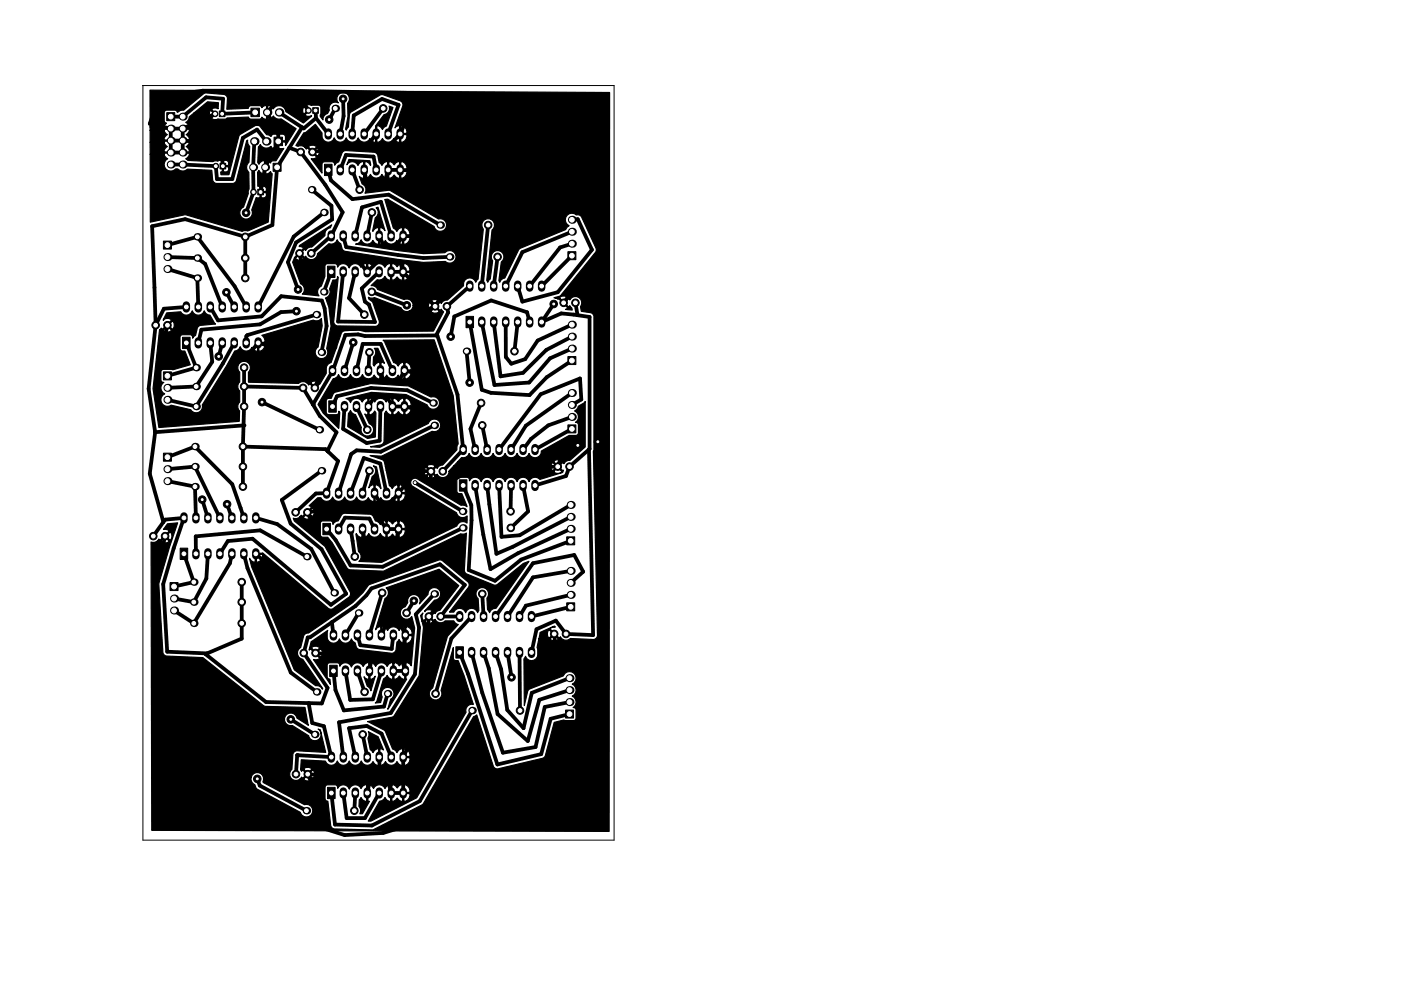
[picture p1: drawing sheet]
<svg xmlns="http://www.w3.org/2000/svg" width="297mm" height="210mm" viewBox="0 0 297 210" stroke-linecap="round" stroke-linejoin="round" font-family="sans-serif">
<path d="M30.2 18.1h100v160.1h-99.9v-160.1" fill="none" stroke="#000" stroke-width=".21"/>
<g fill="#000" stroke="#000" stroke-width=".21">
<path d="M35.3 23.9h1.7v1.7h-1.7zM46.5 23.5h1.2v1.2h-1.2zM46.6 34.6h1.3v1.2h-1.3zM53.2 22.9h1.8v1.8h-1.8zM57.9 34.6h1.7v1.7h-1.7zM58.1 29.1h1.8v1.8h-1.8zM66.3 22.8h1.2v1.2h-1.2zM68.8 34.8h1.6v2.4h-1.6zM34.6 51.1h1.7v1.7h-1.7zM54.6 40.1h1.3v1.2h-1.3zM69.4 56.5h1.6v2.4h-1.6zM120.4 53.4h1.7v1.7h-1.7z"/>
<path d="M38.7 71.5h1.6v2.4h-1.6zM98.8 67.1h1.6v2.4h-1.6zM120.4 75.6h1.7v1.7h-1.7zM34.6 78.9h1.7v1.7h-1.7zM34.6 96.1h1.7v1.7h-1.7zM69.7 85h1.6v2.4h-1.6zM120.4 90.1h1.7v1.7h-1.7zM38.2 116.3h1.6v2.4h-1.6zM68.4 111h1.6v2.4h-1.6zM97.4 101.8h1.6v2.4h-1.6zM120.2 113.9h1.6v1.7h-1.6zM36 123.6h1.7v1.7h-1.7z"/>
<path d="M96.7 137.2h1.5v2.4h-1.5zM120.2 127.9h1.6v1.7h-1.6zM69.9 141.1h1.6v2.4h-1.6zM119.9 150.6h1.7v1.7h-1.7zM69.4 167h1.6v2.4h-1.6z"/>
<circle cx="45.6" cy="24.1" r=".6"/>
<circle cx="45.7" cy="35.2" r=".6"/>
<circle cx="63.7" cy="32.2" r=".8"/>
<circle cx="65.4" cy="23.4" r=".6"/>
<circle cx="66.2" cy="32.2" r=".8"/>
<circle cx="69.8" cy="25.4" r=".8"/>
<circle cx="72.7" cy="21" r=".8"/>
<circle cx="81.2" cy="23" r=".8"/>
<circle cx="52" cy="59" r=".8"/>
<circle cx="52" cy="50.2" r=".8"/>
<circle cx="52" cy="54.7" r=".8"/>
<circle cx="52.2" cy="45.1" r=".8"/>
<circle cx="53.7" cy="40.7" r=".6"/>
<circle cx="63.5" cy="53.7" r=".8"/>
<circle cx="66" cy="53.7" r=".8"/>
<circle cx="76.2" cy="40.2" r=".8"/>
<circle cx="78.8" cy="45.1" r=".8"/>
<circle cx="103.5" cy="47.7" r=".8"/>
<circle cx="105.5" cy="54.5" r=".8"/>
<circle cx="33" cy="69" r=".8"/>
<circle cx="35.5" cy="69" r=".8"/>
<circle cx="46.4" cy="75.6" r=".8"/>
<circle cx="48" cy="62" r=".8"/>
<circle cx="51.8" cy="78" r=".8"/>
<circle cx="62.8" cy="66" r=".8"/>
<circle cx="63.2" cy="61.4" r=".8"/>
<circle cx="74.9" cy="72.6" r=".8"/>
<circle cx="77.2" cy="66.7" r=".8"/>
<circle cx="78.3" cy="74.7" r=".8"/>
<circle cx="78.8" cy="61.9" r=".8"/>
<circle cx="86.2" cy="64.8" r=".8"/>
<circle cx="92.2" cy="65" r=".8"/>
<circle cx="94.7" cy="65" r=".8"/>
<circle cx="95.5" cy="71.4" r=".8"/>
<circle cx="109.1" cy="74.5" r=".8"/>
<circle cx="117.4" cy="64.5" r=".8"/>
<circle cx="119.5" cy="64.2" r=".8"/>
<circle cx="122" cy="64.2" r=".8"/>
<circle cx="51.5" cy="99" r=".8"/>
<circle cx="51.5" cy="94.7" r=".8"/>
<circle cx="51.8" cy="82" r=".8"/>
<circle cx="51.8" cy="86.2" r=".8"/>
<circle cx="55.5" cy="85.3" r=".8"/>
<circle cx="64.2" cy="82.3" r=".8"/>
<circle cx="66.7" cy="82.3" r=".8"/>
<circle cx="77.9" cy="91.2" r=".8"/>
<circle cx="78.3" cy="99.9" r=".8"/>
<circle cx="91.4" cy="100" r=".8"/>
<circle cx="93.9" cy="100" r=".8"/>
<circle cx="99.6" cy="81.2" r=".8"/>
<circle cx="102" cy="85.5" r=".8"/>
<circle cx="102.2" cy="90.2" r=".8"/>
<circle cx="118.2" cy="99" r=".8"/>
<circle cx="120.7" cy="99" r=".8"/>
<circle cx="122.5" cy="94.5" r=".8"/>
<circle cx="126.7" cy="93.7" r=".8"/>
<circle cx="32.5" cy="113.7" r=".8"/>
<circle cx="35" cy="113.7" r=".8"/>
<circle cx="42.9" cy="106" r=".8"/>
<circle cx="48.1" cy="107" r=".8"/>
<circle cx="51.5" cy="103.2" r=".8"/>
<circle cx="62.7" cy="108.7" r=".8"/>
<circle cx="65.2" cy="108.7" r=".8"/>
<circle cx="75.2" cy="118.1" r=".8"/>
<circle cx="88" cy="102.4" r=".4"/>
<circle cx="108.2" cy="108.5" r=".8"/>
<circle cx="108.3" cy="112" r=".8"/>
<circle cx="51.2" cy="127.7" r=".8"/>
<circle cx="51.2" cy="123.5" r=".8"/>
<circle cx="51.2" cy="132.2" r=".8"/>
<circle cx="64.4" cy="138.5" r=".8"/>
<circle cx="66.9" cy="138.5" r=".8"/>
<circle cx="81" cy="125.8" r=".8"/>
<circle cx="86.2" cy="130" r=".8"/>
<circle cx="87.7" cy="127.5" r=".8"/>
<circle cx="90.9" cy="130.8" r=".8"/>
<circle cx="93.4" cy="130.8" r=".8"/>
<circle cx="102.2" cy="126" r=".8"/>
<circle cx="117.5" cy="134.5" r=".8"/>
<circle cx="120" cy="134.5" r=".8"/>
<circle cx="61.6" cy="152.6" r=".8"/>
<circle cx="76.9" cy="155.8" r=".8"/>
<circle cx="77.3" cy="146.8" r=".8"/>
<circle cx="92.3" cy="147.2" r=".8"/>
<circle cx="108.4" cy="143.7" r=".8"/>
<circle cx="110.3" cy="150.7" r=".8"/>
<circle cx="54.5" cy="165.2" r=".8"/>
<circle cx="62.7" cy="164.2" r=".8"/>
<circle cx="65.2" cy="164.2" r=".8"/>
<circle cx="75.1" cy="172" r=".8"/>
</g>
<g fill="#000">
<circle cx="36.2" cy="27.3" r=".85"/>
<circle cx="36.2" cy="29.8" r=".85"/>
<circle cx="36.2" cy="34.9" r=".85"/>
<circle cx="36.2" cy="32.4" r=".85"/>
<circle cx="38.7" cy="34.9" r=".85"/>
<circle cx="38.7" cy="24.7" r=".85"/>
<circle cx="38.7" cy="32.4" r=".85"/>
<circle cx="38.7" cy="29.8" r=".85"/>
<circle cx="38.7" cy="27.3" r=".85"/>
<circle cx="53.7" cy="35.5" r=".85"/>
<circle cx="53.9" cy="30" r=".9"/>
<circle cx="56.2" cy="35.5" r=".85"/>
<circle cx="56.5" cy="30" r=".9"/>
<circle cx="56.6" cy="23.8" r=".9"/>
<circle cx="57.9" cy="26.2" r=".4"/>
<circle cx="59.2" cy="23.8" r=".9"/>
<circle cx="71.1" cy="23" r=".8"/>
<circle cx="100.3" cy="36.9" r=".4"/>
<circle cx="35.5" cy="54.5" r=".85"/>
<circle cx="35.5" cy="57.1" r=".85"/>
<circle cx="41.8" cy="54.7" r=".8"/>
<circle cx="41.8" cy="50.2" r=".8"/>
<circle cx="41.8" cy="59" r=".8"/>
<circle cx="66.1" cy="40.2" r=".8"/>
<circle cx="68.7" cy="45.1" r=".8"/>
<circle cx="93.3" cy="47.7" r=".8"/>
<circle cx="95.3" cy="54.5" r=".8"/>
<circle cx="121.2" cy="49.2" r=".85"/>
<circle cx="121.2" cy="46.6" r=".85"/>
<circle cx="121.2" cy="51.7" r=".85"/>
<circle cx="41.6" cy="78" r=".8"/>
<circle cx="67.1" cy="66.7" r=".8"/>
<circle cx="68.2" cy="74.7" r=".8"/>
<circle cx="68.6" cy="77.5" r=".4"/>
<circle cx="68.7" cy="61.9" r=".8"/>
<circle cx="98.9" cy="74.5" r=".8"/>
<circle cx="121.2" cy="74" r=".85"/>
<circle cx="121.2" cy="71.4" r=".85"/>
<circle cx="121.2" cy="68.9" r=".85"/>
<circle cx="35.5" cy="84.8" r=".85"/>
<circle cx="35.5" cy="99.5" r=".85"/>
<circle cx="35.5" cy="82.3" r=".85"/>
<circle cx="41.3" cy="99" r=".8"/>
<circle cx="41.3" cy="94.7" r=".8"/>
<circle cx="41.6" cy="86.2" r=".8"/>
<circle cx="41.6" cy="82" r=".8"/>
<circle cx="51.6" cy="90.3" r=".4"/>
<circle cx="66.3" cy="85.8" r=".4"/>
<circle cx="67.7" cy="91.2" r=".8"/>
<circle cx="68.2" cy="99.9" r=".8"/>
<circle cx="91.8" cy="85.5" r=".8"/>
<circle cx="92.1" cy="90.2" r=".8"/>
<circle cx="121.2" cy="83.4" r=".85"/>
<circle cx="121.2" cy="85.9" r=".85"/>
<circle cx="121.2" cy="88.5" r=".85"/>
<circle cx="127.9" cy="93.5" r=".4"/>
<circle cx="35.5" cy="102.1" r=".85"/>
<circle cx="41.3" cy="103.2" r=".8"/>
<circle cx="65.1" cy="118.1" r=".8"/>
<circle cx="98.1" cy="108.5" r=".8"/>
<circle cx="98.1" cy="112" r=".8"/>
<circle cx="121" cy="109.7" r=".85"/>
<circle cx="121" cy="107.1" r=".85"/>
<circle cx="121" cy="112.2" r=".85"/>
<circle cx="36.9" cy="129.5" r=".85"/>
<circle cx="36.9" cy="127" r=".85"/>
<circle cx="41.1" cy="132.2" r=".8"/>
<circle cx="41.1" cy="127.7" r=".8"/>
<circle cx="41.1" cy="123.5" r=".8"/>
<circle cx="70.9" cy="125.8" r=".8"/>
<circle cx="76" cy="130" r=".8"/>
<circle cx="92.1" cy="126" r=".8"/>
<circle cx="121" cy="123.7" r=".85"/>
<circle cx="121" cy="121.1" r=".85"/>
<circle cx="121" cy="126.2" r=".85"/>
<circle cx="66.7" cy="155.8" r=".8"/>
<circle cx="67.1" cy="146.8" r=".8"/>
<circle cx="82.2" cy="147.2" r=".8"/>
<circle cx="100.1" cy="150.7" r=".8"/>
<circle cx="120.8" cy="149" r=".85"/>
<circle cx="120.8" cy="146.4" r=".85"/>
<circle cx="120.8" cy="143.9" r=".85"/>
<circle cx="63" cy="160.2" r=".4"/>
<circle cx="65" cy="172" r=".8"/>
</g>
<g fill="none" stroke="#000" stroke-width="1.6">
<path d="M69.6 28v.8M72.1 28v.8M72.1 35.6v.8M74.7 28v.8M74.7 35.6v.8M77.2 28v.8M77.2 35.6v.8M79.8 28v.8M79.8 35.6v.8M82.3 28v.8M82.3 35.6v.8M84.8 28v.8"/>
<path d="M84.8 35.6v.8M70.2 49.7v.8M72.8 49.7v.8M72.8 57.3v.8M75.3 49.7v.8M75.3 57.3v.8M77.8 49.7v.8M77.8 57.3v.8M80.4 49.7v.8M80.4 57.3v.8M82.9 49.7v.8M82.9 57.3v.8"/>
<path d="M85.5 49.7v.8M85.5 57.3v.8M39.5 64.7v.8M42 64.7v.8M42 72.3v.8M44.6 64.7v.8M44.6 72.3v.8M47.1 64.7v.8M47.1 72.3v.8M49.7 64.7v.8M49.7 72.3v.8M52.2 64.7v.8"/>
<path d="M52.2 72.3v.8M54.7 64.7v.8M54.7 72.3v.8M70.5 78.2v.8M73 78.2v.8M75.6 78.2v.8M78.1 78.2v.8M80.7 78.2v.8M83.2 78.2v.8M85.7 78.2v.8M99.6 60.3v.8M102.1 60.3v.8"/>
<path d="M102.1 67.9v.8M104.7 60.3v.8M104.7 67.9v.8M107.2 60.3v.8M107.2 67.9v.8M109.8 60.3v.8M109.8 67.9v.8M112.3 60.3v.8M112.3 67.9v.8M114.8 60.3v.8M114.8 67.9v.8M73 85.8v.8"/>
<path d="M75.6 85.8v.8M78.1 85.8v.8M80.7 85.8v.8M83.2 85.8v.8M85.7 85.8v.8M98.2 95v.8M100.7 95v.8M103.3 95v.8M105.8 95v.8M108.4 95v.8M110.9 95v.8M113.4 95v.8"/>
<path d="M39 109.5v.8M41.5 109.5v.8M41.5 117.1v.8M44.1 109.5v.8M44.1 117.1v.8M46.6 109.5v.8M46.6 117.1v.8M49.2 109.5v.8M49.2 117.1v.8M51.7 109.5v.8M51.7 117.1v.8M54.2 109.5v.8"/>
<path d="M54.2 117.1v.8M69.3 104.2v.8M71.8 104.2v.8M71.8 111.8v.8M74.3 104.2v.8M74.3 111.8v.8M76.9 104.2v.8M76.9 111.8v.8M79.4 104.2v.8M79.4 111.8v.8M82 104.2v.8M82 111.8v.8"/>
<path d="M84.5 104.2v.8M84.5 111.8v.8M100.7 102.6v.8M103.3 102.6v.8M105.8 102.6v.8M108.4 102.6v.8M110.9 102.6v.8M113.4 102.6v.8M70.7 134.3v.8M73.2 134.3v.8M75.8 134.3v.8M78.3 134.3v.8"/>
<path d="M80.9 134.3v.8M83.4 134.3v.8M85.9 134.3v.8M97.4 130.4v.8M100 130.4v.8M100 138v.8M102.5 130.4v.8M102.5 138v.8M105.1 130.4v.8M105.1 138v.8M107.6 130.4v.8M107.6 138v.8"/>
<path d="M110.1 130.4v.8M110.1 138v.8M112.7 130.4v.8M112.7 138v.8M73.2 141.9v.8M75.8 141.9v.8M78.3 141.9v.8M80.9 141.9v.8M83.4 141.9v.8M85.9 141.9v.8M70.3 160.2v.8M72.8 160.2v.8"/>
<path d="M72.8 167.8v.8M75.3 160.2v.8M75.3 167.8v.8M77.9 160.2v.8M77.9 167.8v.8M80.4 160.2v.8M80.4 167.8v.8M83 160.2v.8M83 167.8v.8M85.5 160.2v.8M85.5 167.8v.8"/>
</g>
<g fill="none" stroke="#000" stroke-width=".8">
<path d="M88.7 19.7l-27.7-.5h-18l-9.3 1.3-2 5.7 4.5 1.1M88.7 19.7l-3.9 8.7-2.6 2.9-4.6-.1M88.7 19.7l37.5 18.8 1.6 16.2M36.2 27.3h2.5M36.2 27.3v5.1h2.5v-5.1M36.2 29.8h2.5l8 .7 .6 4.7M45.6 24.1l-6.9 3.2M53.9 30l-.2 5.5v5.2l-1.5 4.4M54.1 23.8l-7 .3 .2-3.2-3.6-.3-5 4.1h-2.5M56.5 30l-2-2.5-3 1.7-2.2 8.8h-3.3l-.3-2.8-9.5-.3M57.9 26.2l-6.3 .1-5.3 4.2M59.2 23.8l5.2 3.4 2.6-2.2"/>
<path d="M61.3 31.3l2.4 .9 5.3 7 3.7 5.8-2.5 5.1-4.2 3.6M64 27l-5.3 8.5-1 12.2-5.7 2.5M65.4 23.4l-1.2-2.1-5.5 .2-2.1 2.3 2.4 4.7v1.5l-2.8 5.5-.9 5.2M66.9 23.4l.1 1.6M67 25l2.6 3.4M69.6 36l.5 2.2 4.6 4 7.7-.9 10.9 6.4M71.1 23l-1.3 2.4M72.1 36l1.3-3.1 5.8 .3 .6 2.8M72.7 21l.1 3.6-.7 3.8M74.7 36l1.6 4.2M74.7 28.4l.3-3.9 6-3.5 3.5 1.2-2.2 6.2M77.2 36l.4 2.1 3.6 1.5 1.1-3.6h2.5l15.5 .9"/>
<path d="M77.6 31.2l-7.2 .4-4.1 .6M79.8 28.4l-2.2 2.8M81.3 23l-4.1 5.4M102.8 26.8v.3l.1-.3-6.2 23.7-11.2-.4-1.7 2.3-2.5-.5-.9-1.8M35.5 52l6.3-1.8 7.9 10.5 2.5 4.4M35.5 54.5l6.3 .2 1.7 1.3 3.6 9.1M35.5 57.1l6.3 1.9 .2 6.1M52 50.2v8.8M52 50.2l-12.7-3.7-7 1.5 .7 21M63.5 53.7l.5 2.3 3.5-.3 8-1.1 2.3 3.1 2.6-2.5 4.4 .2 .7 2.3M66.1 40.2l4.2 3.4 .1 2.9-7.6 4.9-1.8 4.2 2.2 5.8M68.7 45.1l-6.4 5.1-7.6 14.9"/>
<path d="M70.2 57.7l-1.5 4.2M72.8 50.1l.6 2.3 11 1.7 5.4 .6 5.5-.2M72.8 57.7l-1.1 10.5 7.8 .1-1.3-3.7-.8-.6-.7-2.8 3.7-3.5M75.3 57.7l-1.3 5.5 3.3 3.5M75.3 50.1l1.4-6.1 4.1-1.2 2.1 7.3M78.8 45.1l-1 5M82.9 57.7h2.6M85.5 57.7l6.8 7.3M96.6 50.5l1.9 3.3-2.8 5.6-3.4 5.6M103.5 47.7l-1.4 13M105.5 54.5l-.8 6.2M121.2 54.2l-6.4 6.5"/>
<path d="M121.2 51.7l-2.4 .8-6.5 8.2M121.2 49.2l-10.4 4.3-3.6 7.2M121.2 46.6l1.3-.1 3 6.5-7.3 9-7.4 2-1-3.3M127.8 54.7l-3.8 3.5-4.5 6M127.8 54.7l.1 38.8M33 69l-1.5 13.5 1.4 9.2M35.5 69l-1.6 6.8-.5 6.6 .5 5 12.2 1.7 3.4-11.8 2.9-1.7 2.3-2.9 10 2.7 3.9 2.1M39.5 72.7l2.1 5.3-6.1 1.7M39.5 65.1l-4.8 .4-1.7 3.5M44.6 65.1l1.6 2.9 9.3-.9 4.1-4.3 8.7 1 .5 1.6 .5 3.8-1.1 5.5M44.6 72.7l.4 4-3.4 5.3-6.1 .3M47.1 72.7l-.7 2.9"/>
<path d="M48 62l1.7 3.1M49.7 72.7l-2.4 4.4-5.7 9.1-6.1-1.4M51.7 78v8.2l-.2 8.5M62.9 66l-3.3 .2-4.5 2.6-12.4 1.1-.7 2.8M67.1 66.7l-14.7 4.4-.2 .2v1.4M68.6 77.5l-1.9 4.8M74.9 72.6l-1.9 6M75.6 78.6l1.3-5.6h3.8l2.5 5.6M78.3 74.7l-.2 3.9M78.8 61.9l7.5 2.9M80.7 78.6l.7 2.4h3.1l1.2-2.4 6.6 1.5 2.7 8.2M92.3 65l-11.2 4.5-10 .4v3.8l-2.5 3.8"/>
<path d="M92.5 71.2h.2l4.3 12.5 1.2 11.7-4.3 4.6M92.5 71.2l-15.1 .1-1.5-.4-2.7 .2-2.6 7.5-4.3 7.2M98.9 74.5l.7 6.7M99.6 68.3l2.5 14.4 2 .6 8.2 .5 3.6-3.8 5.3-3.5M99.6 60.7l-4.9 4.3 .3 1.3-2.5 4.9M102.1 68.3l2.7 13.4 7.4-.5 4.4-5.2 4.6-2M104.7 68.3l1.4 11.5 4.8-.7 4.9-4.9 5.4-2.8M107.2 68.3v7.4l1.2 1.5 3-1 2.6-4 7.2-3.3M109.8 68.3l-.7 6.2M112.3 68.3l-.5-2.1-7.7-2.5-7.8 3.4-.8 4.3M117.4 64.5l-2.6 3.8 4.2-1.8 6 .7v28l-4.2 3.8-.8 2-6.6 2M122 64.2l.4 2.7"/>
<path d="M32.9 91.7h.1M32.9 91.7l-1.2 8.8 2.9 10.3M35.5 97l5.8-2.3 8 8 2.4 7.2M35.5 99.5l5.8-.5 5.3 10.9M51.5 94.7v8.5M51.5 94.7l17.5 .6 2.7 2.5-2.4 6.8-2.3 .1-4.3 4M51.6 90.3l-18.7 1.4M51.7 82l12.6 .3 3.5 5.9 3.6 3.5-2 4 .2-.3v.4M55.6 85.3l12.1 5.9M68.2 99.9l-8.5 6.2 1.9 5 6.6 5.4 5.2 9.5-3.3 2.3-16.5-14-5.3 .5-1.7 2.7M73 86.2l-.3 4.8 5 3 2.8-.5 .2-7.3M75.6 86.2l2.3 5"/>
<path d="M78.1 86.2l1.4-2.2h2.5l1.2 2.2h2.5l9.3 2.1M78.3 99.9l-1.4 4.7M91.8 85.5l-5.4-2.7-7.7-.5-7.3 1.8-.9 2.1M92.1 90.2l-11.4 5.6-5.1-.3-1.2 .8-2.6 8.3M95 88.3l-.8 4-11.3 14.3h-2.4M102 85.5l-2.2 5.5 .9 4.4M102.2 90.2l1.1 5.2M121.2 91l-7.8 4.4M121.2 88.5l-5 1.7-3.6 2.9-1.7 2.3M121.2 85.9l2-1.2-.2-4.4-8.4 3.3-8.8 11.8M121.2 83.4l-9.7 6.9-3.1 5.1M122.5 94.5l-3.3 1.7-1 2.8-18 .5-6.1 3.4-2.8-.8 .1-2.1-3.1-.1"/>
<path d="M124.9 95.4l.9 39.3-5.8-.2-2.2-2.8-4 1.8-1.1 4.9M127.9 93.5l.1 41.5-1.8 7.2-8.2-3-.5-4.7M127.9 93.5l-1.1 .2M32.5 113.7l2.5-3.5 4-.3-2.2 6.4-2.2 7.6 .9 14.4 8.4 .3M35 113.7l-2.3 10.3 .8 16.8 23.3 22.6 10.2 6.2M35.5 102.1l5.8 1.1 .2 6.7M39 117.5l2.1 6-4.2 .9M41.5 117.5v-3.7l13.7-1.3 9.9 5.6M42.9 106l1.2 3.9M44.1 117.5l-.4 5.2-2.6 5-4.2-.7M48.2 107l1 2.9M49.2 117.5l-.5 2-7.6 12.7-4.2-2.7"/>
<path d="M51.7 117.5l.8 3 9.2 22.2 5.4 4.1M54.2 109.9l4.6 1.3 7.2 5.3 4.9 9.3M71.8 112.2l1.3-2.4 5.2 .2 1.1 2.2M74.3 112.2l.9 5.9M74.3 104.6l2.8-7.4 3.5 1.1 1.4 6.3M78.7 107.8l3.3 4.4h2.5l-.8 4.3-6.2-1-.6-3.3M78.7 107.8l-5.3-.3-8.2 1.2 2.4 5.3 2.6 2.1 5 8.8-.4 2.1-5.7 3.9-14.9-13.4M79.4 104.6l1.1 2M80.5 106.6l-1.8 1.2M88 102.4l10.1 6.1M98.1 112l-17 8.2-6.8-.2-3.1-5.4-1.9-2.4M98.2 103l1.7 4.2 .1 3.2-.6 10.5 5.6 2.3 5.5-4.5 10.5-4"/>
<path d="M100.7 103l1.8 10.4 1.5 7.3 5.8-3.3 11.2-5.2M103.3 103l1.9 14.5 3.6-1.5 12.2-6.3M105.8 103l.5 10.9 3.9-.3 10.8-6.5M108.4 103l-.2 5.5M110.9 103l1.1 5.5-3.7 3.5M51.3 123.5v12l-7.4 3.1M66.9 138.5l11.9 1.4M70.4 132l.3 2.7M75.8 134.7l.6 2.2 6.7 .8 .3-3M76 130l-2.8 4.7M78.8 139.9l-.5 2.4M78.8 139.9l6.3 .1"/>
<path d="M80.9 134.7l1-2.4 2.9-.1 1.1 2.5-.8 5.3M81 125.8l-2.7 8.9M83 132.3l1.8-6.5 8.6-3.1 1.4 2.9-3.9 5.2-1.8 22.4-3.6 7.4v7.6h-2.5l-1-3.5-3.5 .5M85.1 140l.8 2.3h-2.5M87.7 127.5l-1.5 2.5M92.1 126l-4 4.3 .7 2.8-.8 9.9-5.2 8.3-10.9 1.9 .9 7.4M97.4 138.4l1.8 4.6 6.2 19.2 9.4-2.2 2-7.5 4-1M97.4 130.8h-4l5.1-6.7-5.2-4.4-14.6 5.1-1 1.5-2.3 2.3-9.7 6.6h-.4l-.9 3.3 5 7.4-1.2 3.3-11.8-.3-12.8-10.1 .3-.2M100 138.4l2.2 8.6 4.4 12.7 6.9-1.2 2-8.5 5.3-1M100 130.8l-4.3 4.7-3.3 11.7M102.2 126l.3 4.8M102.5 138.4l1.1 3.4 1.9 9.7 6.4 5.7 2.5-8.7 6.4-2.1"/>
<path d="M105.1 138.4l1.1 3.6 1.3 8.6 3.5 3.9 1.8-7.5 8-3.1M107.6 138.4l.9 5.3M110.1 138.4l.1 12.3M121 128.7l-8.3 2.1M121 126.2l-9.5 2.3-1.4 2.3M121 123.7l2.6-2.4-1.8-3.6-8.8 1.8-7.9 11.3M121 121.1l-8 1.4-5.4 8.3M61.7 152.6l5 3.2M65.4 149.2l.8 4.2 2.5 .7 1.6 6.5-7.3-.4-.3 4M70.7 142.3l.4 4.1 1.8 4.3 8.5-.8 .8-2.7M73.2 142.3l1.1 6.2 4.7-.1 1.9-6.1M75.8 142.3l1.5 4.5"/>
<path d="M76.9 155.8l1 4.8M100.1 150.7l-11.1 19.3-10.2 5.1-7.8-.2-.7-6.7M126.3 142l-4.5 22.3-40.5 12.4-8.2 .5-6-1.9-.1-7.1-1.7-4 13.2 1M54.6 165.2l.5 1.5 9.9 5.3M72.8 168.2l.7 5.4h3.9l3-5.4M75.3 168.2l-.2 3.8M75.3 160.6l-1.3-6.1 3.8-.5 3.1 1.7 2.1 4.9M78.5 165.2l-.6 3M80.4 160.6l.1 4.4"/>
</g>
<path d="M31.8 19.1l97.4 .5-.1 156.8-96.9-.2v-11.2h21l.2 1 .6 .5 .6 .9 9.1 5v.1a1.35 1.35 0 0 0 1.7 .8 1.35 1.35 0 0 0 .8-1.7 1.35 1.35 0 0 0-1.6-.9l-8.8-4.7-.1-.2a1.34 1.34 0 0 0-.7-1.8 1.34 1.34 0 0 0-1.8 1h-21l-.2-50a1.2 1.2 0 0 0 1.4-.2h.8v.2a1.05 1.05 0 0 0 1.6-.2l-.8-.9-.8 .9h-.8l.3-.4 .3 .2 .8-.9h.4l.8 .9a.97 .97 0 0 0 0-1.7l-.8 .8h-.4l1-1v-.2l-.6-.2h-.5l.8-1.2 2.2-.2-1.8 5.2-2.2 7.7 .8 14.4a.95 .95 0 0 0 1 1l7.5 .3 13 10.3 8.7 .3 .7 3.8-2.4-1.5a1.35 1.35 0 0 0-1.6-1.1 1.35 1.35 0 0 0-1.1 1.6 1.35 1.35 0 0 0 1.7 1l3.4 2.2 .1 .2a1.34 1.34 0 0 0 2.1 .6 1.34 1.34 0 0 0-.2-2.2l.5 .1 1.2 4.8-6.5-.3-.5 .6-.2 3.3-.3 .3a1.34 1.34 0 0 0 .2 1.8 1.34 1.34 0 0 0 1.8 0h.8l.1 .2a1.05 1.05 0 0 0 1.6-.2l-.8-.9-.9 .9h-.8l.3-.4 .3 .2 .9-.9h.3l.9 .9a.97 .97 0 0 0 0-1.7l-.9 .8h-.3l-.9-.8-.3 .3-.2-.3v-.2h.7l.9 .9 .8-.9-.1-.2a1.05 1.05 0 0 0-1.6 .2h-.7l.2-2 5.1 .3a1.34 1.34 0 0 0 1.3 .9 1.34 1.34 0 0 0 1.2-1 1.33 1.33 0 0 0 1.3 1 1.33 1.33 0 0 0 1.3-1 1.33 1.33 0 0 0 1.2 1 1.33 1.33 0 0 0 1.3-1 1.33 1.33 0 0 0 1.2 1 1.33 1.33 0 0 0 1.3-.8 1.01 1.01 0 0 0 1.2 .7v-3.3l-.2-.2a1.33 1.33 0 0 0-1 .9l-.6-.6-.5-2.5 .2-.5-.1-.9 2.1 1.1 1.1 2.8-.5-.3-.3 .2v3.3l.3 .1a1.33 1.33 0 0 0 .9-.8 1.34 1.34 0 0 0 1.3 .8 1.34 1.34 0 0 0 1.2-.8 1.01 1.01 0 0 0 1.2 .7v-1.5h.2v1.5l.2 .1a1.45 1.45 0 0 0 1.1-1.6h-1.6l.1-1.8h.2v1.5h1.3v-.4a1.1 1.1 0 0 0-1.5-1.1l-.3-.2-.5 .3-.4 .6-.3-.4-.6-.4-1.7-3.9-3.7-1.9 5.5-1.1 5.4-8.5 1-10.2-.3-1.5h.6a.97 .97 0 0 0 1.7 0l-.9-.8-.8 .8h-.6l-.3-1.2 .5-.5-.2 .5v.6l.2 .4h.2l1.9-1.8a.97 .97 0 0 0-1.7 0l-.1-.1 2.1-2.4a1.34 1.34 0 0 0 1.3-1.4 1.34 1.34 0 0 0-1.4-1.3 1.34 1.34 0 0 0-1.2 1.5l-1.9 2 .2-.4a1.35 1.35 0 0 0-1.4-1.6 1.35 1.35 0 0 0-1.2 1.7l-.6 .9-.5 .2a1.35 1.35 0 0 0-.2 2.1 1.35 1.35 0 0 0 2.1-.2l.6 2.4-.7 8.1-.3-.5-.5-.2-.3 .1v3.3l.1 .1-4 6.4 .6-2.2a1.33 1.33 0 0 0 .6-1.8 1.33 1.33 0 0 0-1.9-.5 1.33 1.33 0 0 0-.5 1.8l-.3 1.2-1.1 .1 .3-.4 1.4-4.7 .5-.3 .3-.4 .4 .6 .6 .2 .2-.1v-1.5h.2v1.5l.3 .1 .5-.2 .4-.5 .3 .5 .5 .2 .3-.1v-1.5h-2.5v-1.8h.2v1.5h2.3v-1.5l-.3-.1-.5 .2-.3 .5-.4-.5-.5-.2-.5 .1-.2-.1a1.34 1.34 0 0 0-1 .8 1.34 1.34 0 0 0-1.2-.8 1.34 1.34 0 0 0-1.3 .8 1.01 1.01 0 0 0-1.2-.7v3.3l.4 .1 .8-.6-1 3.1a1.24 1.24 0 0 0-.7-1l-.7-2 .7 .5 .3-.1v-3.3l-.2-.1-.6 .2-.4 .6-.3-.4a1.33 1.33 0 0 0-2.2 .5 1.33 1.33 0 0 0-1.2-.9 1.33 1.33 0 0 0-1.3 .8l-.1-.6-.4-.2h-1.6l-.5 .3v2.6l.1 .4 .5 .2 .1 1.1-3.6-5.3 .8 .1 .4-.2v-.2l-1-1.1h.4l.8 .9a.97 .97 0 0 0 0-1.7l-.8 .8h-.4l-.8-.8-.3 .3-.1-.2 .1-.3h.5l.8 .9 .8-.9a.97 .97 0 0 0-1.6 0h-.5l.4-1.4 3.5-2.4-.1 .5v1.4a1.34 1.34 0 0 0 1.3 .9 1.34 1.34 0 0 0 1.3-1 1.33 1.33 0 0 0 1.2 1 1.33 1.33 0 0 0 1.3-1l.3 .6 .5 .3 .2 .8 .4 .5 7 .9a.91 .91 0 0 0 1.1-.9l.2-1.5 .4-.5 .4 .5 .6 .3 .2-.1v-1.5h.3v1.5l.2 .1a1.45 1.45 0 0 0 1.1-1.6h-1.6v-1.8h.3v1.5h1.3v-.4a1.1 1.1 0 0 0-1.6-1.1l-.2-.2-.6 .3-.4 .6-.2-.4a1.35 1.35 0 0 0-2.2 .4 1.01 1.01 0 0 0-1.2-.7v1.8h-.3v-1.8l-.3-.1-.8 .6 2-6.6a1.31 1.31 0 0 0 .3-2.3l11.2-3.9 4.2 3.4-4 5.3-.6 .2-.5 .5-.3-.2-.8 .8 .8 .8 .3-.2 .1 .2a1.32 1.32 0 0 0 2.1 .1h1.8l.3 .5 .7 .3-2.4 2.6-3.1 10.9a1.34 1.34 0 0 0-.5 1.8 1.34 1.34 0 0 0 1.8 .6 1.34 1.34 0 0 0 .5-1.9l2.6-9.1 .1 2.4 .2 .3 .7 .1 1.3 3.1 2 6.1h-.2a1.31 1.31 0 0 0-1.4 1.7l-10.5 18.2-9.7 4.9h-.5l2.4-4.2 .9-.4 .2-.4a1.01 1.01 0 0 0 1.2 .7v-1.5h.3v1.5l.2 .1 .6-.2 .3-.5 .4 .5 .5 .2 .3-.1v-1.5h.2v1.5l.3 .1a1.48 1.48 0 0 0 1-1.6h-4.1v-1.8h.3v1.5h2.3v-1.5h.2v1.5h1.3v-.4a1.1 1.1 0 0 0-1.5-1.1l-.3-.1-.5 .2-.4 .5-.3-.5-.5-.2-.6 .1-.2-.1a1.33 1.33 0 0 0-1 .8 1.34 1.34 0 0 0-1.2-.8 1.34 1.34 0 0 0-1.2 .8 1.01 1.01 0 0 0-1.2-.7v3.3l.3 .1-1.5 2.6h-.5a1.25 1.25 0 0 0-.2-1.5l.1-1.4 .4-.5 .3 .6 .6 .2 .2-.1v-3.3l-.2-.1a1.33 1.33 0 0 0-.9 .8 1.34 1.34 0 0 0-1.3-.8 1.34 1.34 0 0 0-1.2 .9 1.33 1.33 0 0 0-1.2-.9 1.33 1.33 0 0 0-1.3 .8l-.2-.6-.4-.2-1.8 .1-.3 .4v2.4l.2 .4 .4 .2 .6 4.9a.96 .96 0 0 0 1.1 1l8 .1 10.4-5.3 10.8-18.7 .7-.3 3.4 10.7a.95 .95 0 0 0 1.3 .7l9.5-2.3 .4-.7 1.8-6.8a11.5 11.5 0 0 1 4.3-.5l.3-.5v-1.7l-.1-.3-.5-.2 .2-.1a1.4 1.4 0 0 0-.4-2.3 1.39 1.39 0 0 0 .9-1.3 1.39 1.39 0 0 0-.9-1.3 1.4 1.4 0 0 0 .4-2.2 1.4 1.4 0 0 0-2.3 .5l-7.1 2.8-.4 .4-.7 3.1-.1-9.9 .3-.6a1.33 1.33 0 0 0 1.4 1 1.33 1.33 0 0 0 1.2-1.2 8.1 8.1 0 0 1 .3-3.5h2.4v.3a1.05 1.05 0 0 0 1.6-.3l-.8-.8-.8 .8h-2.4l.2-1.2h1.6l.1 1h.3l.8-.8-.8-.8h-.3l-.1 .6h-1.6l.1-.1 3-1.4 .1 .3h-.6l-.4 .1v.3l1.8 1.8 .3-.2 .1 .2a1.32 1.32 0 0 0 2 .2l4.9 .2 .6-.3 .3-.6-.9-39.1 .1-.4v-27.9a.96 .96 0 0 0-.9-1.1l-1.8-.2-.1-1.1a1.34 1.34 0 0 0-.4-1.9 1.34 1.34 0 0 0-1.9 .5l-.3-.2-.8 .8 .8 .9 .3-.3 .5 .6v.4l-1.4-.1 .4-.2v-.2l-1.8-1.9-.2 .1-.5-.3h.9l.8 .9 .8-.9a.97 .97 0 0 0-1.6 0h-1.3l1.5-.5 7.5-9.4-.1-.8-3-6.5-.5-.4h-.6l-.4-.3a1.4 1.4 0 0 0-1.8 .8 1.4 1.4 0 0 0 .7 1.8l-.4 .3-.4 .5-9.8 4.1-3.1 6.2-.7 .3-.3 .6-.2-.4 .5-3.9a1.34 1.34 0 0 0 .3-1.9 1.34 1.34 0 0 0-1.9-.3 1.34 1.34 0 0 0-.2 1.9l-.6 3.9-.5 .7-.2-.4 1.1-10.7 .3-.3a1.35 1.35 0 0 0-.2-1.8 1.35 1.35 0 0 0-1.8 .1 1.35 1.35 0 0 0-.1 1.8l-1.1 10.6-.5 .7a1.35 1.35 0 0 0-1.7-.9 1.35 1.35 0 0 0-.9 1.6l-3.4 3.1-.9 .2-.4 .5-.3-.2-.9 .8 .9 .8 .3-.2 .4 .6-2.1 4-14.4 .2-1.7-.4-3 .2-.5 .6-2.1 6.1a1.24 1.24 0 0 0-1 1.2v1.1l-1.4 2.3-1 1-1.1-1-.3 .2-.3-.4h.8l.8 .8 .9-.8-.1-.3a1.05 1.05 0 0 0-1.6 .3l-.9-.1a1.29 1.29 0 0 0-1.7 .1l-10.6-.2v-2.2l.2-.1a1.35 1.35 0 0 0-.3-1.9 1.35 1.35 0 0 0-1.8 .2 1.35 1.35 0 0 0 0 1.8v2.1l-.2 .2a1.29 1.29 0 0 0 .2 1.7v2.4l-.2 .2a1.29 1.29 0 0 0 .2 1.7l-.1 2.2-17 1.3-1.3-8.2 1.4-12.4 .9-.1a.97 .97 0 0 0 1.6 0l-.8-.8-.8 .8h-.8l.3-.4 .3 .2 .8-.8h.4l.8 .8a.97 .97 0 0 0 0-1.6l-.8 .8h-.4l1-1a.97 .97 0 0 0-1.6 0l-.1-.1 .7-1.5 3-.2 .2 .3a1.33 1.33 0 0 0 2.3-.6 1.33 1.33 0 0 0 1.2 1 1.33 1.33 0 0 0 1.3-1 1.27 1.27 0 0 0 1.2 1l1.2 1.8-3.5 .4-.4 .6-.3 1.4-.7 .7v-.5l-.3-.2-1.8-.1-.4 .2-.1 .3v2.7l.3 .2 .7 .1 1.2 2.9-3.8 1.1-2-.1-.3 .1-.2 .4v1.7l.2 .4 .4 .1a1.37 1.37 0 0 0 .2 2.5 1.39 1.39 0 0 0-.6 1.9 1.39 1.39 0 0 0 2 .5l4.2 .9 .1 .3a1.34 1.34 0 0 0 1.6 .2 1.34 1.34 0 0 0 .7-1.5l5.1-8.3 1.8-3.1a1.26 1.26 0 0 0 1.1-.9 1.33 1.33 0 0 0 1.2 .9 1.33 1.33 0 0 0 1.3-.8 1.01 1.01 0 0 0 1.2 .7v-1.5h.3v1.5l.2 .1a1.45 1.45 0 0 0 1.1-1.6h-1.6v-.3h1.6l-.2-.9-.5-.5 10.9-3.3 .6 .2a1.2 1.2 0 0 0 1.1-.5l.2 1.5-.9 4.5a1.33 1.33 0 0 0-.3 1.9 1.33 1.33 0 0 0 1.8 .4 1.33 1.33 0 0 0 .4-1.9l.9-4.8-.5-4-.7-2a1.3 1.3 0 0 0 .9-1.9l.7-1.9 .8-.1 .2-.6 .1 .2-1 9.3 .3 .7 .6 .3h7.8a.94 .94 0 0 0 .9-1.3l-1.3-3.8-.8-.6-.1-.4 .5 .2 .8-.2 5.6 2.2 .1 .2a1.29 1.29 0 0 0 1.6 .5h4.7l.1 .3a1.05 1.05 0 0 0 1.6-.3l-.8-.8-.9 .8h-4.7l.7-.5 .2-.7h3.2l.2 1h.2l.9-.8-.9-.8h-.2l-.2 .6h-3.2l-.3-.8h4.1l.9 .8 .8-.8a.97 .97 0 0 0-1.7 0h-4.1l-.8-.6-.8 .2-5.7-2.2a1.25 1.25 0 0 0-1.3-.8l1.3-1.3h.9l.7-.7 .4 .6 .6 .3 .2-.2v-1.5h.3v1.5l.2 .2 .5-.3 .4-.5 .3 .5 .5 .2 .3-.1v-1.5h.3v1.5l.3 .1a1.48 1.48 0 0 0 1-1.6h-4.1v-1.8h.3v1.5h2.2v-1.5h.3v1.5h1.3v-.4a1.1 1.1 0 0 0-1.6-1.1l-.3-.1-.5 .3-.3 .4-.4-.4-.4-.3-.6 .1-.2-.1a1.33 1.33 0 0 0-1 .8 1.34 1.34 0 0 0-1.2-.8 1.34 1.34 0 0 0-1.2 .8 1.01 1.01 0 0 0-1.2-.7v1.8h-.3v-1.8l-.2-.1a1.33 1.33 0 0 0-1 .8 1.34 1.34 0 0 0-1.3-.8 1.34 1.34 0 0 0-1.2 1 1.33 1.33 0 0 0-1.1-1 1.33 1.33 0 0 0-1.3 .8l-.1-.4-.3-.3-1.8-.1-.4 .2-.1 .4v2.1l-.8 2.1a1.33 1.33 0 0 0-.5 2.1l-3.5-.4 .2-.2a1.32 1.32 0 0 0-.6-2l-1.7-4.6 .4-.8h.3v.2a1.05 1.05 0 0 0 1.6-.2l-.8-.9-.8 .9h-.3l1.9-2.1v-.2l-.9-.2 .1-.2 6.8-4.4-.3 .6a1.33 1.33 0 0 0-1.1 1.7l-2.8 2.4-.9 .2-.4 .5-.3-.2-.8 .8 .8 .9 .3-.3 .1 .2a1.34 1.34 0 0 0 1.4 .6 1.34 1.34 0 0 0 1-1.3l2.4-2.1 .5 .1a1.3 1.3 0 0 0 1.3-.9l.3 .5 .4 .3 .4 1.3 .7 .4 10.9 1.6 5.5 .7 4.7-.2a1.35 1.35 0 0 0 1.9-.1 1.35 1.35 0 0 0 0-1.9 1.35 1.35 0 0 0-2 .1l-4.5 .2-5.3-.6-9.1-1.4 .9-.4 .3-.4a1.35 1.35 0 0 0 1.2 .8 1.35 1.35 0 0 0 1.3-.8 1.01 1.01 0 0 0 1.2 .7v-3.3l-.3-.1a1.33 1.33 0 0 0-.9 .8l.5-2.9a1.32 1.32 0 0 0 .1-2.1l.4-.1 1.5 4.9-.8-.6-.3 .1v3.3l.2 .1a1.33 1.33 0 0 0 1-.8 1.34 1.34 0 0 0 1.2 .8 1.34 1.34 0 0 0 1.3-.8 1.01 1.01 0 0 0 1.1 .7v-1.5h.3v1.5l.2 .1a1.45 1.45 0 0 0 1.1-1.6h-1.6v-1.8h.3v1.5h1.3v-.4a1.1 1.1 0 0 0-1.6-1.1l-.2-.1-.6 .2-.3 .6-.3-.4-.5-.3-1.8-6.1h.6l9.8 5.8a1.34 1.34 0 0 0 1.7 1 1.34 1.34 0 0 0 .9-1.7 1.34 1.34 0 0 0-1.6-.9l-10.3-6.1-5.3 .6a1.32 1.32 0 0 0-.6-2l-.6-1.6 .6 .4 .3-.1v-3.3l-.2-.1-.6 .2-.4 .6-.3-.4a1.32 1.32 0 0 0-2 .3l.4-1.2 4.4 .3 .1 1a1.01 1.01 0 0 0-1.2-.7v3.3l.3 .1a1.34 1.34 0 0 0 .9-.8 1.34 1.34 0 0 0 1.3 .8 1.34 1.34 0 0 0 1.2-.8 1.01 1.01 0 0 0 1.2 .7v-1.5h.2v1.5l.2 .1 .6-.2 .4-.5 .3 .5 .5 .2 .3-.1v-1.5h.3v1.5l.3 .1a1.48 1.48 0 0 0 1-1.6h-4.1v-1.8h.2v1.5h2.3v-1.5h.3v1.5h1.3v-.4a1.1 1.1 0 0 0-1.6-1.1l-.3-.1-.5 .2-.3 .5-.4-.5-.5-.2-.5 .1-.2-.1a1.33 1.33 0 0 0-1 .8l-.6-.6-.3-1.6-.5-.5-6.3-.5-.6 .3-.9 2.2-.6 .3-.3 .4v-.5l-.3-.2-1.8-.1-.4 .2-.1 .3v1.9l-2.3-3h.6l.4-.2 .1-.2-1-1 .3-.1 .9 .9a.97 .97 0 0 0 0-1.7l-.9 .8h-.3l-.9-.8-.3 .3-.3-.5h.8l.9 .9 .8-.9a.97 .97 0 0 0-1.7 0h-.8l-.6-.3-.8 .1-.5-.1 1.7-2.7 .5-.2 2-1.6 1.4 1.8a1.4 1.4 0 0 0 .7 1.9 1.4 1.4 0 0 0 1.9-.9 1.33 1.33 0 0 0 1.2 1 1.33 1.33 0 0 0 1.3-1 1.33 1.33 0 0 0 1.3 1 1.33 1.33 0 0 0 1.3-1 1.33 1.33 0 0 0 1.2 1 1.33 1.33 0 0 0 1.2-.8 1.01 1.01 0 0 0 1.2 .7v-3.3l1.9-2.5a1.32 1.32 0 0 0 1-1.8l.8 .3-1.4 4-.6 .3-.2 .4-.4-.6-.6-.3-.2 .2v3.3l.2 .1a1.34 1.34 0 0 0 1-.8 1.34 1.34 0 0 0 1.2 .8 1.34 1.34 0 0 0 1.2-.8 1.01 1.01 0 0 0 1.2 .7v-1.5h.3v1.5l.2 .1a1.45 1.45 0 0 0 1.1-1.6h-1.6v-1.8h.3v1.5h1.3v-.4a1.1 1.1 0 0 0-1.6-1.1l-.3-.1-.7 .4 1.7-4.5a.93 .93 0 0 0-.7-1.3l-3.5-1.2h-.6l-6.2 3.7-.3 .5-.2 2.7-.5 .6-.1-.2 .5-2.7-.1-2.8a1.34 1.34 0 0 0 0-1.9 1.34 1.34 0 0 0-1.9 0 1.34 1.34 0 0 0-.1 1.8 1.32 1.32 0 0 0-1.5 .2 1.32 1.32 0 0 0-.4 1.4l-.4 .7-.7 .5-.2 .8-.6-.7 .1-1.9-.1-.3-.4-.2-1.5 .1-.4-.2h-.5l-.3 .2-.1 .2 .9 .9-.9 .8a.88 .88 0 0 0 1.3 .2l-1.7 1.6-3.7-2.4-.1-.4h3.7l.1 .8h.2l.7-.7-.7-.6h-.2l-.1 .5h-3.7a1.45 1.45 0 0 0-2.5-.2 1.07 1.07 0 0 0-1.2-.6v2.7l.2 .1 .5-.2 .5-.5 .2 .3a1.49 1.49 0 0 0 1.4 .3l3.2 2.1-2.3 3.6v-.6l-.1-.2h-1.3v1.3l.2 .1h.9l-1.7 2.6-.8 .1-.3 .4-.8-.5-.3 .1v2.6l.3 .1 .8-.5 .3 .4-.8 10.3-4.4 1.9-.8-.1-.4 .2-11.9-3.5-7.5 1.5-.1-14.4h3l.1 .4 .7 .6a1.39 1.39 0 0 0-.5 2.1 1.39 1.39 0 0 0 2.1 0l.5 .1a1.45 1.45 0 0 0 2 0l5.2 .2 .2 1.8a.94 .94 0 0 0 1 1h3.3l.6-.3 2.3-8.7 .2-.2 .1 .9 .3 .5-.1 3.3a1.35 1.35 0 0 0 0 2.1v3.6l-.2 .4 .1 .6-1.1 2.8a1.34 1.34 0 0 0-.6 1.8 1.34 1.34 0 0 0 1.8 .7 1.34 1.34 0 0 0 .6-1.8l.9-2.7 .7 .1 .1-.2v-.9h.3v.9l.1 .2 .7-.1 .3-.4v-.5l-.2-.1h-1.2v-1.2h.3v.9h.9l.2-.1-.1-.7-.4-.3h-.5l-.1 .2-.7-.2-.1-3 .3-.4 .5 .7 .5 .1 .2-.1v-2.6l-.2-.1-.5 .1-.5 .7-.3-.4 .2-3.4 .4-.4a1.46 1.46 0 0 0 2.3 .3l.5 .5h.7l.2-.1v-2.8h.2v1.3h1.3l.1-.2-.1-1-.4-.2h-.7l-.2 .1-1.1-.1-.5 .5-.5-.3-.5-.1-1.2-1.6a.95 .95 0 0 0-1.4-.2l-3.2 1.9-2.2 8.4h-1.7v-.6l.3-.2v-.9h.3v.9l.1 .2 .7-.1 .3-.4v-.5l-.2-.1h-1.2v-1.2h.3v.9h.9l.2-.1-.1-.7-.4-.3h-.5l-.1 .2-.9-.2-.3 .2-.7-.1-.4 .2-5.3-.3-.4-.3 .6-.6 .2-.4-.1-.2h-5.2l-.1 .2h-3v-2.5h3l.1 .4 .6 .5-.6 .5-.1 .4 .1 .2h1.2v-2.2h.2v2.2h2.3v-2.2h.3v2.2h1.2l.1-.2-.2-.4-.5-.5 .5-.5 .2-.4-.1-.2h-5.2l-.1 .2h-3v-2.6h3l.1 .5 .6 .5-.6 .5-.1 .4 .1 .2h1.2v-2.3h.2v2.3h2.3v-2.3h.3v2.3h1.2l.1-.2-.2-.4-.5-.5 .5-.5 .2-.5-.1-.2h-5.2l-.1 .2h-3v-.7h3l.1 .3h5.2l.1-.3-.2-.4-.6-.5 .6-.7 .1-.5 1-.8h3.3l.1 .8h.2l.7-.7-.7-.6h-.2l-.1 .5h-3.3l2.9-2.4 2.3 .2-.1 1.3a1.19 1.19 0 0 0-1.2 0l-.1 .2 .9 .8-.9 .9 .1 .2a1.14 1.14 0 0 0 1.2 0l1.5 .1 .4-.3 4.6-.2 .1 .3 .4 .2h1.8l.4-.2 .1-.2 .8 .4 .2-.1v-2.7l-.2-.1-.8 .4-.1-.2-.4-.2h-1.8l-.4 .2-.1 .4-4.6 .2 .1-2.2a.93 .93 0 0 0-.9-1l-3.9-.3-4.5 3.7-.7 .1-.5 .3-.7-.4h-1.9l-.3 .5v1.7l.2 .4 .3 .1-.5 .8h-3zM70.6 80.4a1.24 1.24 0 0 0 1.2-1 1.33 1.33 0 0 0 1.2 1 1.33 1.33 0 0 0 1.3-1 1.33 1.33 0 0 0 1.3 1 1.33 1.33 0 0 0 1.2-1 1.33 1.33 0 0 0 1.3 1 1.33 1.33 0 0 0 1.2-.8 1.01 1.01 0 0 0 1.2 .7v-3.3l-.2-.2a1.33 1.33 0 0 0-1 .9l-.2-.4 .1-1.6a1.28 1.28 0 0 0 .2-1.8h.7l1.4 3.2-.5-.3-.2 .2v3.3l.2 .1 .6-.3 .4-.5 .2 .4a1.35 1.35 0 0 0 2.2-.4 1.01 1.01 0 0 0 1.2 .7v-1.5h.3v1.5l.2 .1a1.45 1.45 0 0 0 1.1-1.6h-1.6v-1.8h.3v1.5h1.3v-.4a1.1 1.1 0 0 0-1.6-1.1l-.2-.2-.6 .3-.4 .6-.2-.4-.7-.4-1.9-4.3-.4-.4 10.9-.1 4 11.8 1 10.3-.1 .3-.1 .9-3.1 3.3-.7 .2-.4 .5-.3-.2-.8 .8 .8 .8 .3-.2 .1 .2a1.34 1.34 0 0 0 1.5 .5 1.34 1.34 0 0 0 .9-1.3h22.2l.1 .3a1.05 1.05 0 0 0 1.6-.3l-.9-.8-.8 .8h-22.2l1.1-1.2h20.5l.2 1h.2l.9-.8-.9-.8h-.2l-.2 .6h-20.5l.7-.8h20.4l.8 .8 .9-.8a.97 .97 0 0 0-1.7 0h-20.4l.9-.9a1.28 1.28 0 0 0 1.6-.9 1.33 1.33 0 0 0 1.2 .9 1.33 1.33 0 0 0 1.3-.9 1.33 1.33 0 0 0 1.3 .9 1.33 1.33 0 0 0 1.2-.9 1.33 1.33 0 0 0 1.3 .9 1.33 1.33 0 0 0 1.3-.9 1.33 1.33 0 0 0 1.3 .9 1.33 1.33 0 0 0 1.2-.9 1.33 1.33 0 0 0 1.3 .9 1.33 1.33 0 0 0 1.3-.9 1.33 1.33 0 0 0 1.5 .9 1.33 1.33 0 0 0 1.1-1.4l5.9-3.3h1.4l.4-.2 .1-.4v-1.7l-.1-.3-.5-.2a1.37 1.37 0 0 0-.2-2.4l.4-.3 .4-.7 1.1-.6 .4-.4v9.6l-3.2 2.9-.9 .2-.4 .5-.3-.2-.9 .8 .9 .8h.2l-.2 .4-4.9 1.5a1.32 1.32 0 0 0-2.2 .5 1.33 1.33 0 0 0-1.3-1 1.33 1.33 0 0 0-1.3 1 1.33 1.33 0 0 0-1.2-1 1.33 1.33 0 0 0-1.3 1 1.33 1.33 0 0 0-1.3-1 1.33 1.33 0 0 0-1.3 1 1.33 1.33 0 0 0-1.2-1 1.33 1.33 0 0 0-1.3 1 1.33 1.33 0 0 0-1.2-1 1.33 1.33 0 0 0-1.3 .8l-.1-.6-.4-.1h-1.8l-.3 .5v2.6l.3 .3h.7l1.1 2.8a1.34 1.34 0 0 0-1.2-.3l-9.3-5.6a.94 .94 0 0 0-1.3 .3 .94 .94 0 0 0 .4 1.3l9.2 5.6v.2a1.38 1.38 0 0 0 2.2 .5v1.5a1.34 1.34 0 0 0-2.1 .6l-16 7.7-4.8-.2a1.31 1.31 0 0 0-.1-2.1l-.5-3.6 .1-.2 .3 .6 .5 .2 .3-.1v-1.8h.3v1.8l.2 .1a1.34 1.34 0 0 0 1-.8 1.34 1.34 0 0 0 1.2 .8 1.34 1.34 0 0 0 1.2-.8 1.01 1.01 0 0 0 1.2 .7v-1.5h.3v1.5l.2 .1 .6-.2 .3-.5 .4 .5 .5 .2 .3-.1v-1.5h.2v1.5l.3 .1a1.48 1.48 0 0 0 1-1.6h-4.1v-1.8h.3v1.5h2.3v-1.5h.2v1.5h1.3v-.4a1.1 1.1 0 0 0-1.5-1.1l-.3-.1-.5 .2-.4 .5-.3-.5-.5-.2-.6 .1-.2-.1a1.33 1.33 0 0 0-1 .8l-.2-.4-.8-.4-.4-.8a.97 .97 0 0 0-1-.6l-5.3-.2-.5 .4-.7 1.2-.9 .4-.2 .4-.2-.6-.4-.2h-1.6l-.4 .3v2.9l.2 .2 1.3 .1 .9 1.1 3.2 5.5 .5 .3 7.4 .2 16.2-7.8h.6l.6-.2-.5 7.9 .3 .6 .3 .2 5.5 2.3h.7l5.8-4.6 1.2-.4-7 10a1.28 1.28 0 0 0-1.4 .9l-.4-.6-.2-2.5a1.34 1.34 0 0 0-.1-1.9 1.34 1.34 0 0 0-1.9 .1 1.34 1.34 0 0 0 .2 1.9l.1 2.5-.3 .4a1.34 1.34 0 0 0-1.3-.8 1.34 1.34 0 0 0-1.2 .9 1.34 1.34 0 0 0-1.2-1 1.34 1.34 0 0 0-1.3 .9h-.9l3.9-5.2a.92 .92 0 0 0-.1-1.4l-5.1-4.2-.8-.3-14.9 5.2-1.3 1.7-2.2 2.2-9.4 6.4-.6 .1-.3 .2-.8 2.8a1.33 1.33 0 0 0-.6 1.4 1.33 1.33 0 0 0 1.1 1.1l4.2 6.2v.1a1.26 1.26 0 0 0-1.5-.7l-4.5-3.4-9-21.8-.5-1.9a1.01 1.01 0 0 0 1.2 .8v-1.6h.3v1.6l.2 .1a1.45 1.45 0 0 0 1.1-1.7h-1.6v-.2l1.6-.1 14 11.8 .3 .2 .6-.1 3.2-2.4a.94 .94 0 0 0 .3-1.4l-5.1-9.3-6.6-5.6-.2-.6 .7 .1 .6-.3h.8a.97 .97 0 0 0 1.7 0l-.8-.8-.9 .8h-.8l.4-.4 .3 .2 .8-.8h.4l.8 .8a.97 .97 0 0 0 0-1.6l-.8 .8h-.4l1-1-.1-.3-.4-.1 1.9-1.7h.6a1.33 1.33 0 0 0 1.3 .8 1.33 1.33 0 0 0 1.2-1 1.33 1.33 0 0 0 1.3 1 1.33 1.33 0 0 0 1.3-1 1.33 1.33 0 0 0 1.2 1 1.33 1.33 0 0 0 1.3-1 1.33 1.33 0 0 0 1.2 1 1.33 1.33 0 0 0 1.3-.8 1.01 1.01 0 0 0 1.2 .7v-3.3l-.3-.1-.8 .6 .7-2.4a1.31 1.31 0 0 0 .3-2.3l.6 .3 1 4.5-.1 .1-.4-.6-.5-.2-.3 .1v3.3l.3 .1a1.34 1.34 0 0 0 .9-.8 1.34 1.34 0 0 0 1.3 .8 1.34 1.34 0 0 0 1.2-.8 1.01 1.01 0 0 0 1.2 .7v-1.5h.2v1.5l.2 .1a1.45 1.45 0 0 0 1.1-1.6h-1.6l.1-1.8h.2v1.5h1.3v-.4a1.1 1.1 0 0 0-1.5-1.1l-.3-.2-.5 .3-.4 .6-.6-.7-.5-2h8.4l.1 .3a1.05 1.05 0 0 0 1.6-.3l-.8-.8-.9 .8h-8.4l-.2-1.2h8l.2 1h.3l.8-.8-.8-.8h-.3l-.2 .6h-8l-.2-.8h8.8l.9 .8 .8-.8-.1-.3a1.05 1.05 0 0 0-1.6 .3h-8.8l-.1-.7a.98 .98 0 0 0-.8-.9l-2.3-.8 2.5 .1 10.6-5.2 .4 .1a1.34 1.34 0 0 0 1.4-1.1 1.34 1.34 0 0 0-1-1.6 1.34 1.34 0 0 0-1.6 .9l-10.3 5.1-1.9-.1 2.2-.4 .6-.5 .2-6.3 .3-.4a1.01 1.01 0 0 0 1.2 .7v-1.5h.2v1.5l.2 .1 .6-.2 .4-.5 .3 .5 .5 .2 .3-.1v-1.5h.3v1.5l.3 .1a1.48 1.48 0 0 0 1-1.6h-4.1v-1.8h.2v1.5h2.3v-1.5h.3v1.5h1.3v-.4a1.1 1.1 0 0 0-1.6-1.1l-.3-.1-.5 .2-.3 .5-.4-.5-.5-.2-.5 .1-.2-.1a1.33 1.33 0 0 0-1 .8 1.34 1.34 0 0 0-1.2-.8 1.34 1.34 0 0 0-1.3 .8 1.01 1.01 0 0 0-1.2-.7v3.3l.3 .1a1.34 1.34 0 0 0 .9-.8l.3 .4-.1 5.1-1.7 .3-4.2-2.5 .2-2.8 .4-.6a1.22 1.22 0 0 0 1.1 .9l1.2 2.7-.1 .2a1.35 1.35 0 0 0 1 1.6 1.35 1.35 0 0 0 1.7-.9 1.35 1.35 0 0 0-.9-1.7l-1-2.1 .5 .2 .2-.1v-3.3l-.2-.1a1.33 1.33 0 0 0-1 .8 1.34 1.34 0 0 0-1.3-.8 1.34 1.34 0 0 0-1.2 .9 1.21 1.21 0 0 0-.9-.8l5.3-1.4 7.4 .5 4.5 2.3a1.35 1.35 0 0 0 1.7 .8 1.35 1.35 0 0 0 .8-1.8 1.35 1.35 0 0 0-1.7-.8l-5-2.3-7.6-.5-7.7 1.8-.5 .4-.4 .9-.7 .1-.3 .2v2.6l.3 .5 1.8 .1 .4-.2 .1-.6 .2 .3-.2 3.4-3.3-3.2-1.1-1.9z" fill="#000" stroke="#000" stroke-width=".25"/>
<g fill="#fff" stroke="#fff" stroke-width=".21">
<circle cx="46.4" cy="75.6" r=".2"/>
<circle cx="69.8" cy="25.4" r=".2"/>
<circle cx="63.2" cy="61.4" r=".2"/>
<circle cx="62.9" cy="66" r=".2"/>
<circle cx="48" cy="62" r=".2"/>
<circle cx="55.5" cy="85.3" r=".2"/>
<circle cx="99.6" cy="81.2" r=".2"/>
<circle cx="72.8" cy="21" r=".2"/>
<circle cx="86.3" cy="64.8" r=".2"/>
<circle cx="95.6" cy="71.4" r=".2"/>
<circle cx="74.9" cy="72.6" r=".2"/>
<circle cx="88" cy="102.4" r=".2"/>
<circle cx="48.2" cy="107" r=".2"/>
<circle cx="54.5" cy="165.2" r=".2"/>
<circle cx="42.9" cy="106" r=".2"/>
<circle cx="61.6" cy="152.6" r=".2"/>
<circle cx="87.7" cy="127.5" r=".2"/>
<circle cx="108.4" cy="143.7" r=".2"/>
<circle cx="122.5" cy="94.5" r=".2"/>
<circle cx="126.7" cy="93.7" r=".2"/>
<circle cx="52.2" cy="45.1" r=".2"/>
<circle cx="117.4" cy="64.5" r=".2"/>
<circle cx="51.7" cy="82" r=".4"/>
<circle cx="41.6" cy="82" r=".4"/>
<circle cx="51.7" cy="78" r=".4"/>
<circle cx="41.6" cy="78" r=".4"/>
<circle cx="41.6" cy="86.2" r=".4"/>
<circle cx="51.7" cy="86.2" r=".4"/>
<circle cx="52" cy="50.2" r=".4"/>
<circle cx="41.8" cy="50.2" r=".4"/>
<circle cx="52" cy="54.7" r=".4"/>
<circle cx="41.8" cy="54.7" r=".4"/>
<circle cx="41.8" cy="59" r=".4"/>
<circle cx="52" cy="59" r=".4"/>
<circle cx="71.1" cy="23" r=".4"/>
<circle cx="81.3" cy="23" r=".4"/>
<circle cx="66.1" cy="40.2" r=".4"/>
<circle cx="76.2" cy="40.2" r=".4"/>
<circle cx="67.1" cy="66.7" r=".4"/>
<circle cx="77.3" cy="66.7" r=".4"/>
<circle cx="78.8" cy="45.1" r=".4"/>
<circle cx="68.7" cy="45.1" r=".4"/>
<circle cx="67.7" cy="91.2" r=".4"/>
<circle cx="77.9" cy="91.2" r=".4"/>
<circle cx="78.3" cy="74.7" r=".4"/>
<circle cx="68.2" cy="74.7" r=".4"/>
<circle cx="98.9" cy="74.5" r=".4"/>
<circle cx="109.1" cy="74.5" r=".4"/>
<circle cx="93.3" cy="47.7" r=".4"/>
<circle cx="103.5" cy="47.7" r=".4"/>
<circle cx="78.8" cy="61.9" r=".4"/>
<circle cx="68.7" cy="61.9" r=".4"/>
<circle cx="105.5" cy="54.5" r=".4"/>
<circle cx="95.3" cy="54.5" r=".4"/>
<circle cx="91.8" cy="85.5" r=".4"/>
<circle cx="102" cy="85.5" r=".4"/>
<circle cx="108.2" cy="108.5" r=".4"/>
<circle cx="98.1" cy="108.5" r=".4"/>
<circle cx="41.1" cy="127.7" r=".4"/>
<circle cx="51.2" cy="127.7" r=".4"/>
<circle cx="51.3" cy="123.5" r=".4"/>
<circle cx="41.1" cy="123.5" r=".4"/>
<circle cx="51.3" cy="132.2" r=".4"/>
<circle cx="41.1" cy="132.2" r=".4"/>
<circle cx="41.3" cy="94.7" r=".4"/>
<circle cx="51.5" cy="94.7" r=".4"/>
<circle cx="51.5" cy="99" r=".4"/>
<circle cx="41.3" cy="99" r=".4"/>
<circle cx="41.3" cy="103.2" r=".4"/>
<circle cx="51.5" cy="103.2" r=".4"/>
<circle cx="78.3" cy="99.9" r=".4"/>
<circle cx="68.2" cy="99.9" r=".4"/>
<circle cx="65.1" cy="118.1" r=".4"/>
<circle cx="75.2" cy="118.1" r=".4"/>
<circle cx="67.1" cy="146.8" r=".4"/>
<circle cx="77.3" cy="146.8" r=".4"/>
<circle cx="81" cy="125.8" r=".4"/>
<circle cx="70.9" cy="125.8" r=".4"/>
<circle cx="65" cy="172" r=".4"/>
<circle cx="75.1" cy="172" r=".4"/>
<circle cx="76.9" cy="155.8" r=".4"/>
<circle cx="66.7" cy="155.8" r=".4"/>
<circle cx="102.2" cy="90.2" r=".4"/>
<circle cx="92.1" cy="90.2" r=".4"/>
<circle cx="98.1" cy="112" r=".4"/>
<circle cx="108.3" cy="112" r=".4"/>
<circle cx="82.2" cy="147.2" r=".4"/>
<circle cx="92.4" cy="147.2" r=".4"/>
<circle cx="86.2" cy="130" r=".4"/>
<circle cx="76" cy="130" r=".4"/>
<circle cx="100.1" cy="150.7" r=".4"/>
<circle cx="110.2" cy="150.7" r=".4"/>
<circle cx="102.2" cy="126" r=".4"/>
<circle cx="92.1" cy="126" r=".4"/>
<circle cx="39.5" cy="72.7" r=".4"/>
<circle cx="54.7" cy="65.1" r=".4"/>
<circle cx="42" cy="72.7" r=".4"/>
<circle cx="52.2" cy="65.1" r=".4"/>
<circle cx="44.6" cy="72.7" r=".4"/>
<circle cx="49.7" cy="65.1" r=".4"/>
<circle cx="47.1" cy="72.7" r=".4"/>
<circle cx="47.1" cy="65.1" r=".4"/>
<circle cx="49.7" cy="72.7" r=".4"/>
<circle cx="44.6" cy="65.1" r=".4"/>
<circle cx="52.2" cy="72.7" r=".4"/>
<circle cx="42" cy="65.1" r=".4"/>
<circle cx="54.7" cy="72.7" r=".4"/>
<circle cx="39.5" cy="65.1" r=".4"/>
<circle cx="69.6" cy="28.4" r=".4"/>
<circle cx="84.8" cy="36" r=".4"/>
<circle cx="72.1" cy="28.4" r=".4"/>
<circle cx="82.3" cy="36" r=".4"/>
<circle cx="74.7" cy="28.4" r=".4"/>
<circle cx="79.8" cy="36" r=".4"/>
<circle cx="77.2" cy="28.4" r=".4"/>
<circle cx="77.2" cy="36" r=".4"/>
<circle cx="79.8" cy="28.4" r=".4"/>
<circle cx="74.7" cy="36" r=".4"/>
<circle cx="82.3" cy="28.4" r=".4"/>
<circle cx="72.1" cy="36" r=".4"/>
<circle cx="84.8" cy="28.4" r=".4"/>
<circle cx="69.6" cy="36" r=".4"/>
<circle cx="70.2" cy="50.1" r=".4"/>
<circle cx="85.5" cy="57.7" r=".4"/>
<circle cx="72.8" cy="50.1" r=".4"/>
<circle cx="82.9" cy="57.7" r=".4"/>
<circle cx="75.3" cy="50.1" r=".4"/>
<circle cx="80.4" cy="57.7" r=".4"/>
<circle cx="77.8" cy="50.1" r=".4"/>
<circle cx="77.8" cy="57.7" r=".4"/>
<circle cx="80.4" cy="50.1" r=".4"/>
<circle cx="75.3" cy="57.7" r=".4"/>
<circle cx="82.9" cy="50.1" r=".4"/>
<circle cx="72.8" cy="57.7" r=".4"/>
<circle cx="85.5" cy="50.1" r=".4"/>
<circle cx="70.2" cy="57.7" r=".4"/>
<circle cx="70.5" cy="86.2" r=".4"/>
<circle cx="85.7" cy="78.6" r=".4"/>
<circle cx="73" cy="86.2" r=".4"/>
<circle cx="83.2" cy="78.6" r=".4"/>
<circle cx="75.6" cy="86.2" r=".4"/>
<circle cx="80.7" cy="78.6" r=".4"/>
<circle cx="78.1" cy="86.2" r=".4"/>
<circle cx="78.1" cy="78.6" r=".4"/>
<circle cx="80.7" cy="86.2" r=".4"/>
<circle cx="75.6" cy="78.6" r=".4"/>
<circle cx="83.2" cy="86.2" r=".4"/>
<circle cx="73" cy="78.6" r=".4"/>
<circle cx="85.7" cy="86.2" r=".4"/>
<circle cx="70.5" cy="78.6" r=".4"/>
<circle cx="99.6" cy="60.7" r=".4"/>
<circle cx="114.8" cy="68.3" r=".4"/>
<circle cx="102.1" cy="60.7" r=".4"/>
<circle cx="112.3" cy="68.3" r=".4"/>
<circle cx="104.7" cy="60.7" r=".4"/>
<circle cx="109.8" cy="68.3" r=".4"/>
<circle cx="107.2" cy="60.7" r=".4"/>
<circle cx="107.2" cy="68.3" r=".4"/>
<circle cx="109.8" cy="60.7" r=".4"/>
<circle cx="104.7" cy="68.3" r=".4"/>
<circle cx="112.3" cy="60.7" r=".4"/>
<circle cx="102.1" cy="68.3" r=".4"/>
<circle cx="114.8" cy="60.7" r=".4"/>
<circle cx="99.6" cy="68.3" r=".4"/>
<circle cx="98.2" cy="95.4" r=".4"/>
<circle cx="113.4" cy="103" r=".4"/>
<circle cx="100.7" cy="95.4" r=".4"/>
<circle cx="110.9" cy="103" r=".4"/>
<circle cx="103.3" cy="95.4" r=".4"/>
<circle cx="108.4" cy="103" r=".4"/>
<circle cx="105.8" cy="95.4" r=".4"/>
<circle cx="105.8" cy="103" r=".4"/>
<circle cx="108.4" cy="95.4" r=".4"/>
<circle cx="103.3" cy="103" r=".4"/>
<circle cx="110.9" cy="95.4" r=".4"/>
<circle cx="100.7" cy="103" r=".4"/>
<circle cx="113.4" cy="95.4" r=".4"/>
<circle cx="98.2" cy="103" r=".4"/>
<circle cx="39" cy="117.5" r=".4"/>
<circle cx="54.2" cy="109.9" r=".4"/>
<circle cx="41.5" cy="117.5" r=".4"/>
<circle cx="51.7" cy="109.9" r=".4"/>
<circle cx="44.1" cy="117.5" r=".4"/>
<circle cx="49.2" cy="109.9" r=".4"/>
<circle cx="46.6" cy="117.5" r=".4"/>
<circle cx="46.6" cy="109.9" r=".4"/>
<circle cx="49.2" cy="117.5" r=".4"/>
<circle cx="44.1" cy="109.9" r=".4"/>
<circle cx="51.7" cy="117.5" r=".4"/>
<circle cx="41.5" cy="109.9" r=".4"/>
<circle cx="54.2" cy="117.5" r=".4"/>
<circle cx="39" cy="109.9" r=".4"/>
<circle cx="69.3" cy="112.2" r=".4"/>
<circle cx="84.5" cy="104.6" r=".4"/>
<circle cx="71.8" cy="112.2" r=".4"/>
<circle cx="82" cy="104.6" r=".4"/>
<circle cx="74.3" cy="112.2" r=".4"/>
<circle cx="79.4" cy="104.6" r=".4"/>
<circle cx="76.9" cy="112.2" r=".4"/>
<circle cx="76.9" cy="104.6" r=".4"/>
<circle cx="79.4" cy="112.2" r=".4"/>
<circle cx="74.3" cy="104.6" r=".4"/>
<circle cx="82" cy="112.2" r=".4"/>
<circle cx="71.8" cy="104.6" r=".4"/>
<circle cx="84.5" cy="112.2" r=".4"/>
<circle cx="69.3" cy="104.6" r=".4"/>
<circle cx="70.7" cy="142.3" r=".4"/>
<circle cx="85.9" cy="134.7" r=".4"/>
<circle cx="73.2" cy="142.3" r=".4"/>
<circle cx="83.4" cy="134.7" r=".4"/>
<circle cx="75.8" cy="142.3" r=".4"/>
<circle cx="80.9" cy="134.7" r=".4"/>
<circle cx="78.3" cy="142.3" r=".4"/>
<circle cx="78.3" cy="134.7" r=".4"/>
<circle cx="80.9" cy="142.3" r=".4"/>
<circle cx="75.8" cy="134.7" r=".4"/>
<circle cx="83.4" cy="142.3" r=".4"/>
<circle cx="73.2" cy="134.7" r=".4"/>
<circle cx="85.9" cy="142.3" r=".4"/>
<circle cx="70.7" cy="134.7" r=".4"/>
<circle cx="70.2" cy="160.6" r=".4"/>
<circle cx="85.5" cy="168.2" r=".4"/>
<circle cx="72.8" cy="160.6" r=".4"/>
<circle cx="82.9" cy="168.2" r=".4"/>
<circle cx="75.3" cy="160.6" r=".4"/>
<circle cx="80.4" cy="168.2" r=".4"/>
<circle cx="77.9" cy="160.6" r=".4"/>
<circle cx="77.9" cy="168.2" r=".4"/>
<circle cx="80.4" cy="160.6" r=".4"/>
<circle cx="75.3" cy="168.2" r=".4"/>
<circle cx="82.9" cy="160.6" r=".4"/>
<circle cx="72.8" cy="168.2" r=".4"/>
<circle cx="85.5" cy="160.6" r=".4"/>
<circle cx="70.2" cy="168.2" r=".4"/>
<circle cx="97.5" cy="138.4" r=".4"/>
<circle cx="112.7" cy="130.8" r=".4"/>
<circle cx="100" cy="138.4" r=".4"/>
<circle cx="110.2" cy="130.8" r=".4"/>
<circle cx="102.5" cy="138.4" r=".4"/>
<circle cx="107.6" cy="130.8" r=".4"/>
<circle cx="105.1" cy="138.4" r=".4"/>
<circle cx="105.1" cy="130.8" r=".4"/>
<circle cx="107.6" cy="138.4" r=".4"/>
<circle cx="102.5" cy="130.8" r=".4"/>
<circle cx="110.2" cy="138.4" r=".4"/>
<circle cx="100" cy="130.8" r=".4"/>
<circle cx="112.7" cy="138.4" r=".4"/>
<circle cx="97.5" cy="130.8" r=".4"/>
<circle cx="120.7" cy="151.5" r=".5"/>
<circle cx="120.7" cy="149" r=".5"/>
<circle cx="120.7" cy="146.4" r=".5"/>
<circle cx="120.7" cy="143.9" r=".5"/>
<circle cx="121.3" cy="83.4" r=".5"/>
<circle cx="121.3" cy="85.9" r=".5"/>
<circle cx="121.3" cy="88.5" r=".5"/>
<circle cx="121.3" cy="91" r=".5"/>
<circle cx="121" cy="114.7" r=".5"/>
<circle cx="121" cy="112.2" r=".5"/>
<circle cx="121" cy="109.7" r=".5"/>
<circle cx="121" cy="107.1" r=".5"/>
<circle cx="121.3" cy="46.6" r=".5"/>
<circle cx="121.3" cy="49.2" r=".5"/>
<circle cx="121.3" cy="51.7" r=".5"/>
<circle cx="121.3" cy="54.2" r=".5"/>
<circle cx="121.3" cy="76.5" r=".5"/>
<circle cx="121.3" cy="74" r=".5"/>
<circle cx="121.3" cy="71.4" r=".5"/>
<circle cx="121.3" cy="68.9" r=".5"/>
<circle cx="121" cy="128.7" r=".5"/>
<circle cx="121" cy="126.2" r=".5"/>
<circle cx="121" cy="123.7" r=".5"/>
<circle cx="121" cy="121.1" r=".5"/>
<circle cx="45.6" cy="24.1" r=".3"/>
<circle cx="47.1" cy="24.1" r=".3"/>
<circle cx="33" cy="69" r=".4"/>
<circle cx="35.5" cy="69" r=".4"/>
<circle cx="66.9" cy="23.4" r=".3"/>
<circle cx="65.4" cy="23.4" r=".3"/>
<circle cx="35" cy="113.7" r=".4"/>
<circle cx="32.5" cy="113.7" r=".4"/>
<circle cx="53.7" cy="40.7" r=".3"/>
<circle cx="55.3" cy="40.7" r=".3"/>
<circle cx="91.4" cy="100" r=".4"/>
<circle cx="93.9" cy="100" r=".4"/>
<circle cx="120" cy="134.5" r=".4"/>
<circle cx="117.5" cy="134.5" r=".4"/>
<circle cx="47.3" cy="35.2" r=".3"/>
<circle cx="45.7" cy="35.2" r=".3"/>
<circle cx="93.4" cy="130.8" r=".4"/>
<circle cx="90.9" cy="130.8" r=".4"/>
<circle cx="64.2" cy="82.3" r=".4"/>
<circle cx="66.7" cy="82.3" r=".4"/>
<circle cx="118.2" cy="99" r=".4"/>
<circle cx="120.7" cy="99" r=".4"/>
<circle cx="94.8" cy="65" r=".4"/>
<circle cx="92.2" cy="65" r=".4"/>
<circle cx="122" cy="64.2" r=".4"/>
<circle cx="119.5" cy="64.2" r=".4"/>
<circle cx="65.3" cy="164.2" r=".4"/>
<circle cx="62.7" cy="164.2" r=".4"/>
<circle cx="66.3" cy="32.2" r=".4"/>
<circle cx="63.7" cy="32.2" r=".4"/>
<circle cx="65.2" cy="108.7" r=".4"/>
<circle cx="62.7" cy="108.7" r=".4"/>
<circle cx="63.5" cy="53.7" r=".4"/>
<circle cx="66" cy="53.7" r=".4"/>
<circle cx="64.4" cy="138.5" r=".4"/>
<circle cx="66.9" cy="138.5" r=".4"/>
<circle cx="58.8" cy="35.5" r=".5"/>
<circle cx="56.2" cy="35.5" r=".5"/>
<circle cx="53.7" cy="35.5" r=".5"/>
<circle cx="36.2" cy="24.7" r=".5"/>
<circle cx="38.7" cy="24.7" r=".5"/>
<circle cx="36.2" cy="27.3" r=".5"/>
<circle cx="38.7" cy="27.3" r=".5"/>
<circle cx="36.2" cy="29.8" r=".5"/>
<circle cx="38.7" cy="29.8" r=".5"/>
<circle cx="36.2" cy="32.4" r=".5"/>
<circle cx="38.7" cy="32.4" r=".5"/>
<circle cx="36.2" cy="34.9" r=".5"/>
<circle cx="38.7" cy="34.9" r=".5"/>
<circle cx="59.2" cy="23.8" r=".5"/>
<circle cx="56.6" cy="23.8" r=".5"/>
<circle cx="54.1" cy="23.8" r=".5"/>
<circle cx="59" cy="30" r=".5"/>
<circle cx="56.5" cy="30" r=".5"/>
<circle cx="53.9" cy="30" r=".5"/>
<circle cx="35.5" cy="84.8" r=".5"/>
<circle cx="35.5" cy="82.3" r=".5"/>
<circle cx="35.5" cy="79.7" r=".5"/>
<circle cx="35.5" cy="52" r=".5"/>
<circle cx="35.5" cy="54.5" r=".5"/>
<circle cx="35.5" cy="57.1" r=".5"/>
<circle cx="36.9" cy="129.5" r=".5"/>
<circle cx="36.9" cy="127" r=".5"/>
<circle cx="36.9" cy="124.4" r=".5"/>
<circle cx="35.5" cy="97" r=".5"/>
<circle cx="35.5" cy="99.5" r=".5"/>
<circle cx="35.5" cy="102.1" r=".5"/>
</g>
</svg>
